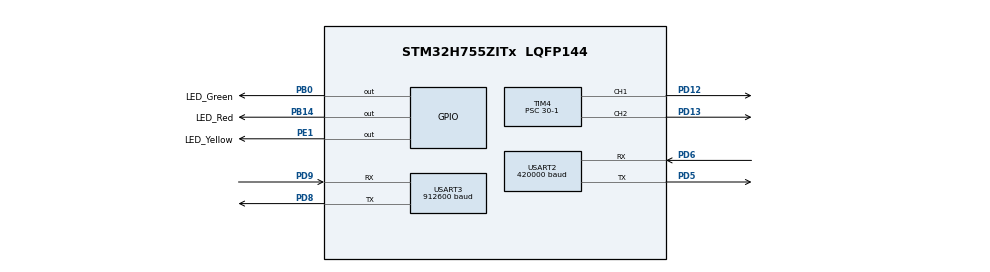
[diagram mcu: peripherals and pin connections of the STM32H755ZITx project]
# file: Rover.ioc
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CORTEX_M7.CPU_ICache=Enabled
CORTEX_M7.default_mode_Activation=0
CortexM4.IPs=BDMA,CORTEX_M4\:I,DEBUG,DMA,FATFS_M4\:I,FREERTOS_M4\:I,GPIO,IWDG2\:I,MDMA,NVIC2\:I,OPENAMP_M4\:I,PDM2PCM_M4\:I,PWR,RCC,RESMGR_UTILITY,SYS_M4\:I,USB_DEVICE_M4\:I,USB_HOST_M4\:I,VREFBUF,WWDG2\:I
CortexM7.IPs=BDMA\:I,CORTEX_M7\:I,DEBUG\:I,DMA\:I,FATFS_M7\:I,FREERTOS_M7\:I,GPIO\:I,IWDG1\:I,MDMA\:I,NVIC1\:I,OPENAMP_M7\:I,PDM2PCM_M7\:I,PWR\:I,RCC\:I,RESMGR_UTILITY\:I,SYS\:I,USB_DEVICE_M7\:I,USB_HOST_M7\:I,VREFBUF\:I,WWDG1\:I,TIM2\:I,TIM4\:I,USART2\:I,USART3\:I
CortexM7.Pins=PB0,PB14,PE1
Dma.Request0=USART2_RX
Dma.USART2_RX.0.Direction=DMA_PERIPH_TO_MEMORY
Dma.USART2_RX.0.EventEnable=DISABLE
Dma.USART2_RX.0.FIFOMode=DMA_FIFOMODE_DISABLE
Dma.USART2_RX.0.Instance=DMA1_Stream0
Dma.USART2_RX.0.MemDataAlignment=DMA_MDATAALIGN_BYTE
Dma.USART2_RX.0.MemInc=DMA_MINC_ENABLE
Dma.USART2_RX.0.Mode=DMA_NORMAL
Dma.USART2_RX.0.PeriphDataAlignment=DMA_PDATAALIGN_BYTE
Dma.USART2_RX.0.PeriphInc=DMA_PINC_DISABLE
Dma.USART2_RX.0.Polarity=HAL_DMAMUX_REQ_GEN_RISING
Dma.USART2_RX.0.Priority=DMA_PRIORITY_LOW
Dma.USART2_RX.0.RequestNumber=1
Dma.USART2_RX.0.SignalID=NONE
Dma.USART2_RX.0.SyncEnable=DISABLE
Dma.USART2_RX.0.SyncPolarity=HAL_DMAMUX_SYNC_NO_EVENT
Dma.USART2_RX.0.SyncRequestNumber=1
Dma.USART2_RX.0.SyncSignalID=NONE
Mcu.Family=STM32H7
Mcu.Name=STM32H755ZITx
Mcu.Package=LQFP144
NVIC1.DMA1_Stream0_IRQn=true\:0\:0\:false\:false\:true\:false\:true\:true
NVIC1.PriorityGroup=NVIC_PRIORITYGROUP_4
NVIC1.USART2_IRQn=true\:0\:0\:false\:false\:true\:true\:true\:true
NVIC2.PriorityGroup=NVIC_PRIORITYGROUP_4
PB0.GPIO_Label=LED_Green
PB0.PinAttribute=CortexM7
PB0.Signal=GPIO_Output
PB14.GPIO_Label=LED_Red
PB14.PinAttribute=CortexM7
PB14.Signal=GPIO_Output
PD12.PinAttribute=CortexM7
PD12.Signal=S_TIM4_CH1
PD13.PinAttribute=CortexM7
PD13.Signal=S_TIM4_CH2
PD5.Mode=Asynchronous
PD5.PinAttribute=CortexM7
PD5.Signal=USART2_TX
PD6.Mode=Asynchronous
PD6.PinAttribute=CortexM7
PD6.Signal=USART2_RX
PD8.Mode=Asynchronous
PD8.PinAttribute=CortexM7
PD8.Signal=USART3_TX
PD9.Mode=Asynchronous
PD9.PinAttribute=CortexM7
PD9.Signal=USART3_RX
PE1.GPIO_Label=LED_Yellow
PE1.PinAttribute=CortexM7
PE1.Signal=GPIO_Output
PH0-OSC_IN\ (PH0).Mode=HSE-External-Oscillator
PH0-OSC_IN\ (PH0).PinAttribute=Free
PH0-OSC_IN\ (PH0).Signal=RCC_OSC_IN
PH1-OSC_OUT\ (PH1).Mode=HSE-External-Oscillator
PH1-OSC_OUT\ (PH1).PinAttribute=Free
PH1-OSC_OUT\ (PH1).Signal=RCC_OSC_OUT
ProjectManager.HeapSize=M4-0x200,M7-0x200
ProjectManager.StackSize=M4-0x400,M7-0x400
ProjectManager.TargetToolchain=STM32CubeIDE
RCC.ADCFreq_Value=16125000
RCC.APB1Freq_Value=100000000
RCC.APB2Freq_Value=100000000
RCC.APB3Freq_Value=100000000
RCC.APB4Freq_Value=100000000
RCC.CortexFreq_Value=400000000
RCC.D1PPRE=RCC_APB3_DIV2
RCC.D2PPRE1=RCC_APB1_DIV2
RCC.D2PPRE2=RCC_APB2_DIV2
RCC.D3PPRE=RCC_APB4_DIV2
RCC.DIVM1=2
RCC.DIVN1=200
RCC.HCLKFreq_Value=200000000
RCC.HPRE=RCC_HCLK_DIV2
RCC.HSE_VALUE=8000000
RCC.PLLSourceVirtual=RCC_PLLSOURCE_HSE
RCC.PWR_Regulator_Voltage_Scale=PWR_REGULATOR_VOLTAGE_SCALE1
RCC.SYSCLKFreq_VALUE=400000000
RCC.SYSCLKSource=RCC_SYSCLKSOURCE_PLLCLK
RCC.USBFreq_Value=400000000
SH.S_TIM4_CH1.0=TIM4_CH1,PWM Generation1 CH1
SH.S_TIM4_CH2.0=TIM4_CH2,PWM Generation2 CH2
TIM2.Prescaler=200-1
TIM4.AutoReloadPreload=TIM_AUTORELOAD_PRELOAD_ENABLE
TIM4.Channel-PWM\ Generation1\ CH1=TIM_CHANNEL_1
TIM4.Channel-PWM\ Generation2\ CH2=TIM_CHANNEL_2
TIM4.Period=20202-1
TIM4.Prescaler=30-1
USART2.BaudRate=420000
USART2.VirtualMode-Asynchronous=VM_ASYNC
USART3.BaudRate=912600
USART3.VirtualMode-Asynchronous=VM_ASYNC
VP_TIM2_VS_ClockSourceINT.Mode=Internal
VP_TIM4_VS_ClockSourceINT.Mode=Internal
board=custom

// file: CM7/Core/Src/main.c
/* USER CODE BEGIN Header */
/**
  ******************************************************************************
  * @file           : main.c
  * @brief          : Main program body
  ******************************************************************************
  * @attention
  *
  * Copyright (c) 2023 STMicroelectronics.
  * All rights reserved.
  *
  * This software is licensed under terms that can be found in the LICENSE file
  * in the root directory of this software component.
  * If no LICENSE file comes with this software, it is provided AS-IS.
  *
  ******************************************************************************
  */
/* USER CODE END Header */
#include "main.h"

/* USER CODE BEGIN PD */

#ifndef HSEM_ID_0
#define HSEM_ID_0 (0U) /* HW semaphore 0*/
#endif

/* USER CODE END PD */

TIM_HandleTypeDef htim2;
TIM_HandleTypeDef htim4;

UART_HandleTypeDef huart2;
UART_HandleTypeDef huart3;
DMA_HandleTypeDef hdma_usart2_rx;

/* USER CODE BEGIN PV */
uint8_t rx_buf[CRSF_MAX_FRAME];
PwmRcChannels_t rc_pwm_raw;
FilteredRcChannels_t rc_pwm_filtered;
LpfData_t* lpf;
/* USER CODE END PV */

void SystemClock_Config(void);
static void MX_GPIO_Init(void);
static void MX_DMA_Init(void);
static void MX_USART3_UART_Init(void);
static void MX_TIM4_Init(void);
static void MX_USART2_UART_Init(void);
static void MX_TIM2_Init(void);

int main(void)
{
/* USER CODE BEGIN Boot_Mode_Sequence_0 */
  int32_t timeout;
/* USER CODE END Boot_Mode_Sequence_0 */

  /* Enable I-Cache---------------------------------------------------------*/
  SCB_EnableICache();

/* USER CODE BEGIN Boot_Mode_Sequence_1 */
  /* Wait until CPU2 boots and enters in stop mode or timeout*/
  timeout = 0xFFFF;
  while((__HAL_RCC_GET_FLAG(RCC_FLAG_D2CKRDY) != RESET) && (timeout-- > 0));
  if ( timeout < 0 )
  {
  Error_Handler();
  }
/* USER CODE END Boot_Mode_Sequence_1 */
  /* MCU Configuration--------------------------------------------------------*/

  /* Reset of all peripherals, Initializes the Flash interface and the Systick. */
  HAL_Init();

  /* Configure the system clock */
  SystemClock_Config();
/* USER CODE BEGIN Boot_Mode_Sequence_2 */
/* When system initialization is finished, Cortex-M7 will release Cortex-M4 by means of
HSEM notification */
/*HW semaphore Clock enable*/
__HAL_RCC_HSEM_CLK_ENABLE();
/*Take HSEM */
HAL_HSEM_FastTake(HSEM_ID_0);
/*Release HSEM in order to notify the CPU2(CM4)*/
HAL_HSEM_Release(HSEM_ID_0,0);
/* wait until CPU2 wakes up from stop mode */
timeout = 0xFFFF;
while((__HAL_RCC_GET_FLAG(RCC_FLAG_D2CKRDY) == RESET) && (timeout-- > 0));
if ( timeout < 0 )
{
Error_Handler();
}
/* USER CODE END Boot_Mode_Sequence_2 */

  /* Initialize all configured peripherals */
  MX_GPIO_Init();
  MX_DMA_Init();
  MX_USART3_UART_Init();
  MX_TIM4_Init();
  MX_USART2_UART_Init();
  MX_TIM2_Init();

  /* Infinite loop */
  while (1)
  {

  }
}

void SystemClock_Config(void)
{
  RCC_OscInitTypeDef RCC_OscInitStruct = {0};
  RCC_ClkInitTypeDef RCC_ClkInitStruct = {0};

  /** Supply configuration update enable
  */
  HAL_PWREx_ConfigSupply(PWR_LDO_SUPPLY);

  /** Configure the main internal regulator output voltage
  */

  while(!__HAL_PWR_GET_FLAG(PWR_FLAG_VOSRDY)) {}

  /** Initializes the RCC Oscillators according to the specified parameters
  * in the RCC_OscInitTypeDef structure.
  */
  RCC_OscInitStruct.OscillatorType = RCC_OSCILLATORTYPE_HSI;
  RCC_OscInitStruct.HSIState = RCC_HSI_DIV1;
  RCC_OscInitStruct.HSICalibrationValue = RCC_HSICALIBRATION_DEFAULT;
  RCC_OscInitStruct.PLL.PLLState = RCC_PLL_ON;
  RCC_OscInitStruct.PLL.PLLSource = RCC_PLLSOURCE_HSI;
  RCC_OscInitStruct.PLL.PLLM = 4;
  RCC_OscInitStruct.PLL.PLLN = 60;
  RCC_OscInitStruct.PLL.PLLP = 2;
  RCC_OscInitStruct.PLL.PLLQ = 2;
  RCC_OscInitStruct.PLL.PLLR = 2;
  RCC_OscInitStruct.PLL.PLLRGE = RCC_PLL1VCIRANGE_3;
  RCC_OscInitStruct.PLL.PLLVCOSEL = RCC_PLL1VCOWIDE;
  RCC_OscInitStruct.PLL.PLLFRACN = 0;
  if (HAL_RCC_OscConfig(&RCC_OscInitStruct) != HAL_OK)
  {
    Error_Handler();
  }

  /** Initializes the CPU, AHB and APB buses clocks
  */
  RCC_ClkInitStruct.ClockType = RCC_CLOCKTYPE_HCLK|RCC_CLOCKTYPE_SYSCLK
                              |RCC_CLOCKTYPE_PCLK1|RCC_CLOCKTYPE_PCLK2
                              |RCC_CLOCKTYPE_D3PCLK1|RCC_CLOCKTYPE_D1PCLK1;
  RCC_ClkInitStruct.SYSCLKSource = RCC_SYSCLKSOURCE_PLLCLK;
  RCC_ClkInitStruct.SYSCLKDivider = RCC_SYSCLK_DIV1;
  RCC_ClkInitStruct.AHBCLKDivider = RCC_HCLK_DIV2;
  RCC_ClkInitStruct.APB3CLKDivider = RCC_APB3_DIV2;
  RCC_ClkInitStruct.APB1CLKDivider = RCC_APB1_DIV2;
  RCC_ClkInitStruct.APB2CLKDivider = RCC_APB2_DIV2;
  RCC_ClkInitStruct.APB4CLKDivider = RCC_APB4_DIV2;

  if (HAL_RCC_ClockConfig(&RCC_ClkInitStruct, FLASH_LATENCY_0) != HAL_OK)
  {
    Error_Handler();
  }
}

static void MX_TIM2_Init(void)
{

  TIM_ClockConfigTypeDef sClockSourceConfig = {0};
  TIM_MasterConfigTypeDef sMasterConfig = {0};

  htim2.Instance = TIM2;
  htim2.Init.Prescaler = 200-1;
  htim2.Init.CounterMode = TIM_COUNTERMODE_UP;
  htim2.Init.Period = 4294967295;
  htim2.Init.ClockDivision = TIM_CLOCKDIVISION_DIV1;
  htim2.Init.AutoReloadPreload = TIM_AUTORELOAD_PRELOAD_DISABLE;
  if (HAL_TIM_Base_Init(&htim2) != HAL_OK)
  {
    Error_Handler();
  }
  sClockSourceConfig.ClockSource = TIM_CLOCKSOURCE_INTERNAL;
  if (HAL_TIM_ConfigClockSource(&htim2, &sClockSourceConfig) != HAL_OK)
  {
    Error_Handler();
  }
  sMasterConfig.MasterOutputTrigger = TIM_TRGO_RESET;
  sMasterConfig.MasterSlaveMode = TIM_MASTERSLAVEMODE_DISABLE;
  if (HAL_TIMEx_MasterConfigSynchronization(&htim2, &sMasterConfig) != HAL_OK)
  {
    Error_Handler();
  }

}

static void MX_TIM4_Init(void)
{

  TIM_ClockConfigTypeDef sClockSourceConfig = {0};
  TIM_MasterConfigTypeDef sMasterConfig = {0};
  TIM_OC_InitTypeDef sConfigOC = {0};

  htim4.Instance = TIM4;
  htim4.Init.Prescaler = 30-1;
  htim4.Init.CounterMode = TIM_COUNTERMODE_UP;
  htim4.Init.Period = 20202-1;
  htim4.Init.ClockDivision = TIM_CLOCKDIVISION_DIV1;
  htim4.Init.AutoReloadPreload = TIM_AUTORELOAD_PRELOAD_ENABLE;
  if (HAL_TIM_Base_Init(&htim4) != HAL_OK)
  {
    Error_Handler();
  }
  sClockSourceConfig.ClockSource = TIM_CLOCKSOURCE_INTERNAL;
  if (HAL_TIM_ConfigClockSource(&htim4, &sClockSourceConfig) != HAL_OK)
  {
    Error_Handler();
  }
  if (HAL_TIM_PWM_Init(&htim4) != HAL_OK)
  {
    Error_Handler();
  }
  sMasterConfig.MasterOutputTrigger = TIM_TRGO_RESET;
  sMasterConfig.MasterSlaveMode = TIM_MASTERSLAVEMODE_DISABLE;
  if (HAL_TIMEx_MasterConfigSynchronization(&htim4, &sMasterConfig) != HAL_OK)
  {
    Error_Handler();
  }
  sConfigOC.OCMode = TIM_OCMODE_PWM1;
  sConfigOC.Pulse = 0;
  sConfigOC.OCPolarity = TIM_OCPOLARITY_HIGH;
  sConfigOC.OCFastMode = TIM_OCFAST_DISABLE;
  if (HAL_TIM_PWM_ConfigChannel(&htim4, &sConfigOC, TIM_CHANNEL_1) != HAL_OK)
  {
    Error_Handler();
  }
  if (HAL_TIM_PWM_ConfigChannel(&htim4, &sConfigOC, TIM_CHANNEL_2) != HAL_OK)
  {
    Error_Handler();
  }
  HAL_TIM_MspPostInit(&htim4);

}

static void MX_USART2_UART_Init(void)
{

  huart2.Instance = USART2;
  huart2.Init.BaudRate = 420000;
  huart2.Init.WordLength = UART_WORDLENGTH_8B;
  huart2.Init.StopBits = UART_STOPBITS_1;
  huart2.Init.Parity = UART_PARITY_NONE;
  huart2.Init.Mode = UART_MODE_TX_RX;
  huart2.Init.HwFlowCtl = UART_HWCONTROL_NONE;
  huart2.Init.OverSampling = UART_OVERSAMPLING_16;
  huart2.Init.OneBitSampling = UART_ONE_BIT_SAMPLE_DISABLE;
  huart2.Init.ClockPrescaler = UART_PRESCALER_DIV1;
  huart2.AdvancedInit.AdvFeatureInit = UART_ADVFEATURE_NO_INIT;
  if (HAL_UART_Init(&huart2) != HAL_OK)
  {
    Error_Handler();
  }
  if (HAL_UARTEx_SetTxFifoThreshold(&huart2, UART_TXFIFO_THRESHOLD_1_8) != HAL_OK)
  {
    Error_Handler();
  }
  if (HAL_UARTEx_SetRxFifoThreshold(&huart2, UART_RXFIFO_THRESHOLD_1_8) != HAL_OK)
  {
    Error_Handler();
  }
  if (HAL_UARTEx_DisableFifoMode(&huart2) != HAL_OK)
  {
    Error_Handler();
  }

}

static void MX_USART3_UART_Init(void)
{

  huart3.Instance = USART3;
  huart3.Init.BaudRate = 921600;
  huart3.Init.WordLength = UART_WORDLENGTH_8B;
  huart3.Init.StopBits = UART_STOPBITS_1;
  huart3.Init.Parity = UART_PARITY_NONE;
  huart3.Init.Mode = UART_MODE_TX_RX;
  huart3.Init.HwFlowCtl = UART_HWCONTROL_NONE;
  huart3.Init.OverSampling = UART_OVERSAMPLING_16;
  huart3.Init.OneBitSampling = UART_ONE_BIT_SAMPLE_DISABLE;
  huart3.Init.ClockPrescaler = UART_PRESCALER_DIV1;
  huart3.AdvancedInit.AdvFeatureInit = UART_ADVFEATURE_NO_INIT;
  if (HAL_UART_Init(&huart3) != HAL_OK)
  {
    Error_Handler();
  }
  if (HAL_UARTEx_SetTxFifoThreshold(&huart3, UART_TXFIFO_THRESHOLD_1_8) != HAL_OK)
  {
    Error_Handler();
  }
  if (HAL_UARTEx_SetRxFifoThreshold(&huart3, UART_RXFIFO_THRESHOLD_1_8) != HAL_OK)
  {
    Error_Handler();
  }
  if (HAL_UARTEx_DisableFifoMode(&huart3) != HAL_OK)
  {
    Error_Handler();
  }

}

static void MX_DMA_Init(void)
{

  /* DMA controller clock enable */
  __HAL_RCC_DMA1_CLK_ENABLE();

  /* DMA interrupt init */
  /* DMA1_Stream0_IRQn interrupt configuration */
  HAL_NVIC_SetPriority(DMA1_Stream0_IRQn, 0, 0);
  HAL_NVIC_EnableIRQ(DMA1_Stream0_IRQn);

}

static void MX_GPIO_Init(void)
{
  GPIO_InitTypeDef GPIO_InitStruct = {0};

  /* GPIO Ports Clock Enable */
  __HAL_RCC_GPIOB_CLK_ENABLE();
  __HAL_RCC_GPIOD_CLK_ENABLE();
  __HAL_RCC_GPIOE_CLK_ENABLE();

  /*Configure GPIO pin Output Level */
  HAL_GPIO_WritePin(GPIOB, LED_Green_Pin|LED_Red_Pin, GPIO_PIN_RESET);

  /*Configure GPIO pin Output Level */
  HAL_GPIO_WritePin(LED_Yellow_GPIO_Port, LED_Yellow_Pin, GPIO_PIN_RESET);

  /*Configure GPIO pins : LED_Green_Pin LED_Red_Pin */
  GPIO_InitStruct.Pin = LED_Green_Pin|LED_Red_Pin;
  GPIO_InitStruct.Mode = GPIO_MODE_OUTPUT_PP;
  GPIO_InitStruct.Pull = GPIO_NOPULL;
  GPIO_InitStruct.Speed = GPIO_SPEED_FREQ_LOW;
  HAL_GPIO_Init(GPIOB, &GPIO_InitStruct);

  /*Configure GPIO pin : LED_Yellow_Pin */
  GPIO_InitStruct.Pin = LED_Yellow_Pin;
  GPIO_InitStruct.Mode = GPIO_MODE_OUTPUT_PP;
  GPIO_InitStruct.Pull = GPIO_NOPULL;
  GPIO_InitStruct.Speed = GPIO_SPEED_FREQ_LOW;
  HAL_GPIO_Init(LED_Yellow_GPIO_Port, &GPIO_InitStruct);

}

void Error_Handler(void)
{
  __disable_irq();
  while (1)
  {
  }
}
